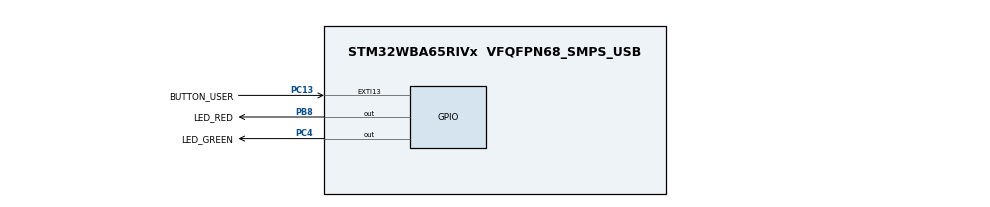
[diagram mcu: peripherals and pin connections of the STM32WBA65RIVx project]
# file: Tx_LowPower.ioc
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CORTEX_M33_NS.userName=CORTEX_M33
Mcu.Family=STM32WBA
Mcu.Name=STM32WBA65RIVx
Mcu.Package=VFQFPN68_SMPS_USB
NVIC.EXTI13_IRQn=true\:0\:0\:false\:false\:true\:false\:true\:true\:true
NVIC.PriorityGroup=NVIC_PRIORITYGROUP_4
NVIC.TIM17_IRQn=true\:15\:0\:false\:false\:true\:false\:false\:true\:true
NVIC.TimeBase=TIM17_IRQn
NVIC.TimeBaseIP=TIM17
OSC_IN.Mode=HSE-External-Oscillator
OSC_IN.PinAttribute=CortexM33
OSC_IN.Signal=RCC_OSC_IN
OSC_OUT.Mode=HSE-External-Oscillator
OSC_OUT.PinAttribute=CortexM33
OSC_OUT.Signal=RCC_OSC_OUT
PB8.GPIO_Label=LED_RED
PB8.GPIO_Speed=GPIO_SPEED_FREQ_HIGH
PB8.PinAttribute=Free
PB8.PinState=GPIO_PIN_SET
PB8.Signal=GPIO_Output
PC13.GPIO_Label=BUTTON_USER
PC13.GPIO_ModeDefaultEXTI=GPIO_MODE_IT_FALLING
PC13.GPIO_PuPd=GPIO_PULLUP
PC13.PinAttribute=Free
PC13.Signal=GPXTI13
PC4.GPIO_Label=LED_GREEN
PC4.GPIO_Speed=GPIO_SPEED_FREQ_HIGH
PC4.PinAttribute=Free
PC4.PinState=GPIO_PIN_SET
PC4.Signal=GPIO_Output
PWR.PowerMode=PWR_SMPS_SUPPLY
ProjectManager.HeapSize=0x200
ProjectManager.StackSize=0x400
ProjectManager.TargetToolchain=EWARM V9.60
RCC.ADCFreq_Value=100000000
RCC.AHB5CLKDivider=DIV4
RCC.AHBFreq_Value=100000000
RCC.APB1Freq_Value=100000000
RCC.APB1TimFreq_Value=100000000
RCC.APB2Freq_Value=100000000
RCC.APB2TimFreq_Value=100000000
RCC.APB3Freq_Value=96000000
RCC.CortexFreq_Value=12500000
RCC.DACCLockSelection=RCC_DAC1CLKSOURCE_LSI
RCC.DACCLockSelectionVirtual=RCC_DAC1CLKSOURCE_LSI
RCC.DACCLockSelectionVirtualString=RCC_DAC1CLKSOURCE_LSI
RCC.EPOD_VALUE=4000000
RCC.FLatency=FLASH_LATENCY_3
RCC.HCLKFreq_Value=100000000
RCC.HSE_VALUE=32000000
RCC.HSI48_VALUE=48000000
RCC.HSI_VALUE=16000000
RCC.LSE_VALUE=32768
RCC.LSI1_VALUE=32000
RCC.LSI2_VALUE=32000
RCC.LSIDIV_VALUE=32000
RCC.MSISDIV=RCC_MSI_DIV1
RCC.MSI_VALUE=4000000
RCC.PLL2FRACN=0
RCC.PLL3FRACN=0
RCC.PLLFRACN=4096
RCC.PLLM=2
RCC.PLLN=12
RCC.PLLSourceVirtual=RCC_PLLSOURCE_HSE
RCC.PWR_Regulator_Voltage_Scale=PWR_REGULATOR_VOLTAGE_SCALE1
RCC.SYSCLKFreq_VALUE=100000000
RCC.SYSCLKSourceVirtual=RCC_SYSCLKSOURCE_PLLCLK
RCC.USBFreq_Value=96000000
RCC.VCOOutputFreq_Value=200000000
THREADX.TX_APP_CREATION=1
THREADX.TX_APP_GENERATE_INIT_CODE=true
THREADX.TX_APP_MEM_POOL_SIZE=(2 * 1024)
THREADX.TX_APP_SEM_CREATION=1
THREADX.TX_APP_THREAD_ENTRY=MainThread_Entry
THREADX.TX_APP_THREAD_NAME=Main Thread
THREADX.TX_APP_THREAD_PRIO=10
THREADX.TX_LOW_POWER=1
THREADX.TX_SEMAPHORE_NAME=Semaphore
VP_CORTEX_M33_NS_VS_Hclk.Mode=Hclk_Mode
VP_ICACHE_VS_ICACHE.Mode=DirectMappedCache
VP_MEMORYMAP_VS_MEMORYMAP.Mode=CurAppReg
VP_PWR_VS_SECSignals.Mode=Security/Privilege
VP_SYS_VS_tim17.Mode=TIM17
VP_THREADX_VS_RTOSJjThreadXJjCoreJjDefault.Mode=Core_Default
VP_THREADX_VS_RTOSJjThreadXJjLow_Power_Support.Mode=Low_Power_Support
board=custom

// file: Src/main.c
/* USER CODE BEGIN Header */
/**
  ******************************************************************************
  * @file           : main.c
  * @brief          : Main program body
  ******************************************************************************
  * @attention
  *
  * Copyright (c) 2024 STMicroelectronics.
  * All rights reserved.
  *
  * This software is licensed under terms that can be found in the LICENSE file
  * in the root directory of this software component.
  * If no LICENSE file comes with this software, it is provided AS-IS.
  *
  ******************************************************************************
  */
/* USER CODE END Header */
#include "app_threadx.h"
#include "main.h"

void SystemClock_Config(void);
static void MX_GPIO_Init(void);
static void MX_ICACHE_Init(void);

int main(void)
{

  /* MCU Configuration--------------------------------------------------------*/

  /* Reset of all peripherals, Initializes the Flash interface and the Systick. */
  HAL_Init();

  /* Configure the system clock */
  SystemClock_Config();

  /* Initialize all configured peripherals */
  MX_GPIO_Init();
  MX_ICACHE_Init();

  MX_ThreadX_Init();

  /* We should never get here as control is now taken by the scheduler */

  /* Infinite loop */
  while (1)
  {

  }
}

void SystemClock_Config(void)
{
  RCC_OscInitTypeDef RCC_OscInitStruct = {0};
  RCC_ClkInitTypeDef RCC_ClkInitStruct = {0};

  /** Supply configuration update enable
  */
  HAL_PWREx_ConfigSupply(PWR_LDO_SUPPLY);

  /** Configure the main internal regulator output voltage
  */
  if (HAL_PWREx_ControlVoltageScaling(PWR_REGULATOR_VOLTAGE_SCALE1) != HAL_OK)
  {
    Error_Handler();
  }

  /** Initializes the CPU, AHB and APB busses clocks
  */
  RCC_OscInitStruct.OscillatorType = RCC_OSCILLATORTYPE_HSE;
  RCC_OscInitStruct.HSEState = RCC_HSE_ON;
  RCC_OscInitStruct.HSEDiv = RCC_HSE_DIV1;
  RCC_OscInitStruct.PLL1.PLLState = RCC_PLL_ON;
  RCC_OscInitStruct.PLL1.PLLSource = RCC_PLLSOURCE_HSE;
  RCC_OscInitStruct.PLL1.PLLM = 2;
  RCC_OscInitStruct.PLL1.PLLN = 12;
  RCC_OscInitStruct.PLL1.PLLP = 2;
  RCC_OscInitStruct.PLL1.PLLQ = 2;
  RCC_OscInitStruct.PLL1.PLLR = 2;
  RCC_OscInitStruct.PLL1.PLLFractional = 4096;
  if (HAL_RCC_OscConfig(&RCC_OscInitStruct) != HAL_OK)
  {
    Error_Handler();
  }

  /** Initializes the CPU, AHB and APB busses clocks
  */
  RCC_ClkInitStruct.ClockType = RCC_CLOCKTYPE_HCLK|RCC_CLOCKTYPE_SYSCLK
                              |RCC_CLOCKTYPE_PCLK1|RCC_CLOCKTYPE_PCLK2
                              |RCC_CLOCKTYPE_PCLK7|RCC_CLOCKTYPE_HCLK5;
  RCC_ClkInitStruct.SYSCLKSource = RCC_SYSCLKSOURCE_PLLCLK;
  RCC_ClkInitStruct.AHBCLKDivider = RCC_SYSCLK_DIV1;
  RCC_ClkInitStruct.APB1CLKDivider = RCC_HCLK_DIV1;
  RCC_ClkInitStruct.APB2CLKDivider = RCC_HCLK_DIV1;
  RCC_ClkInitStruct.APB7CLKDivider = RCC_HCLK_DIV1;
  RCC_ClkInitStruct.AHB5_PLL1_CLKDivider = RCC_SYSCLK_PLL1_DIV4;
  RCC_ClkInitStruct.AHB5_HSEHSI_CLKDivider = RCC_SYSCLK_HSEHSI_DIV1;

  if (HAL_RCC_ClockConfig(&RCC_ClkInitStruct, FLASH_LATENCY_3) != HAL_OK)
  {
    Error_Handler();
  }
}

static void MX_ICACHE_Init(void)
{

  /** Enable instruction cache in 1-way (direct mapped cache)
  */
  if (HAL_ICACHE_ConfigAssociativityMode(ICACHE_1WAY) != HAL_OK)
  {
    Error_Handler();
  }
  if (HAL_ICACHE_Enable() != HAL_OK)
  {
    Error_Handler();
  }

}

static void MX_GPIO_Init(void)
{
  GPIO_InitTypeDef GPIO_InitStruct = {0};

  /* GPIO Ports Clock Enable */
  __HAL_RCC_GPIOB_CLK_ENABLE();
  __HAL_RCC_GPIOC_CLK_ENABLE();

  /*Configure GPIO pin Output Level */
  HAL_GPIO_WritePin(LED_RED_GPIO_Port, LED_RED_Pin, GPIO_PIN_SET);

  /*Configure GPIO pin Output Level */
  HAL_GPIO_WritePin(LED_GREEN_GPIO_Port, LED_GREEN_Pin, GPIO_PIN_SET);

  /*Configure GPIO pin : LED_RED_Pin */
  GPIO_InitStruct.Pin = LED_RED_Pin;
  GPIO_InitStruct.Mode = GPIO_MODE_OUTPUT_PP;
  GPIO_InitStruct.Pull = GPIO_NOPULL;
  GPIO_InitStruct.Speed = GPIO_SPEED_FREQ_HIGH;
  HAL_GPIO_Init(LED_RED_GPIO_Port, &GPIO_InitStruct);

  /*Configure GPIO pin : BUTTON_USER_Pin */
  GPIO_InitStruct.Pin = BUTTON_USER_Pin;
  GPIO_InitStruct.Mode = GPIO_MODE_IT_FALLING;
  GPIO_InitStruct.Pull = GPIO_PULLUP;
  HAL_GPIO_Init(BUTTON_USER_GPIO_Port, &GPIO_InitStruct);

  /*Configure GPIO pin : LED_GREEN_Pin */
  GPIO_InitStruct.Pin = LED_GREEN_Pin;
  GPIO_InitStruct.Mode = GPIO_MODE_OUTPUT_PP;
  GPIO_InitStruct.Pull = GPIO_NOPULL;
  GPIO_InitStruct.Speed = GPIO_SPEED_FREQ_HIGH;
  HAL_GPIO_Init(LED_GREEN_GPIO_Port, &GPIO_InitStruct);

  /* EXTI interrupt init*/
  HAL_NVIC_SetPriority(EXTI13_IRQn, 0, 0);
  HAL_NVIC_EnableIRQ(EXTI13_IRQn);

}

void HAL_TIM_PeriodElapsedCallback(TIM_HandleTypeDef *htim)
{
  if (htim->Instance == TIM17)
  {
    HAL_IncTick();
  }
}

void Error_Handler(void)
{
  /* USER CODE BEGIN Error_Handler_Debug */
  /* User can add his own implementation to report the HAL error return state */
  HAL_GPIO_WritePin(LED_GREEN_GPIO_Port, LED_GREEN_Pin, GPIO_PIN_SET);
  while (1)
  {
    HAL_GPIO_TogglePin(LED_RED_GPIO_Port, LED_RED_Pin);
    HAL_Delay(1000);
  }
  /* USER CODE END Error_Handler_Debug */
}
